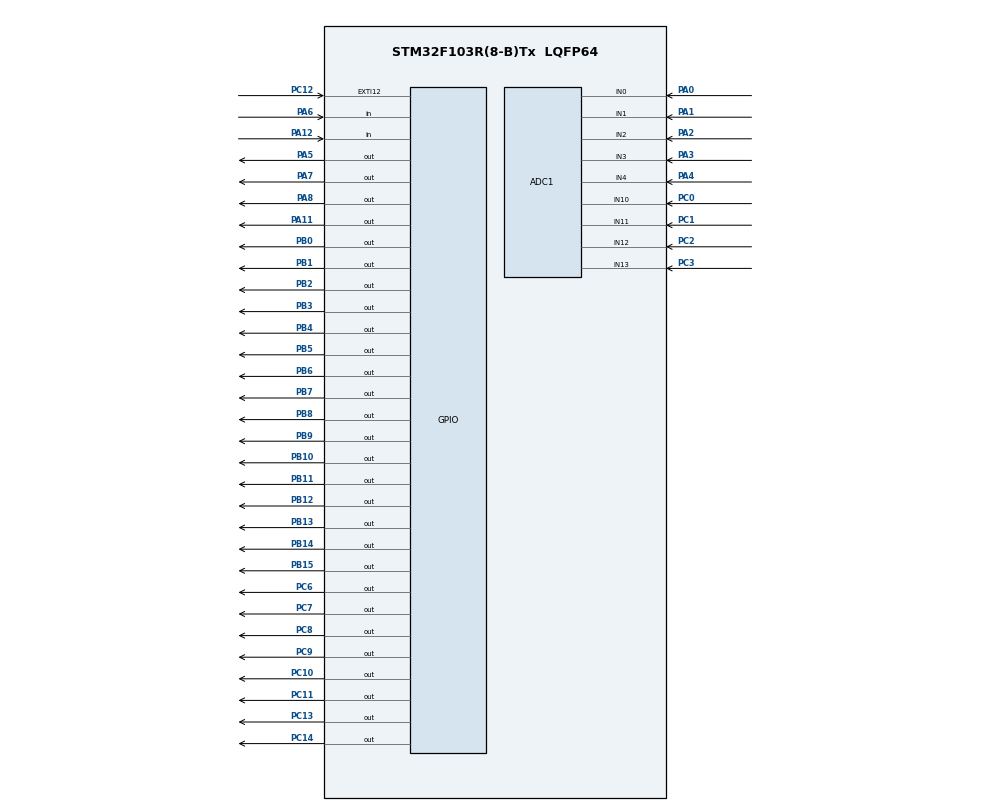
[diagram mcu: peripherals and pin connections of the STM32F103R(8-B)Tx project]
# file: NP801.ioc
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ADC1.Channel-0\#ChannelRegularConversion=ADC_CHANNEL_10
ADC1.Channel-1\#ChannelRegularConversion=ADC_CHANNEL_11
ADC1.Channel-2\#ChannelRegularConversion=ADC_CHANNEL_12
ADC1.Channel-3\#ChannelRegularConversion=ADC_CHANNEL_13
ADC1.Channel-4\#ChannelRegularConversion=ADC_CHANNEL_0
ADC1.Channel-5\#ChannelRegularConversion=ADC_CHANNEL_1
ADC1.Channel-6\#ChannelRegularConversion=ADC_CHANNEL_2
ADC1.Channel-7\#ChannelRegularConversion=ADC_CHANNEL_3
ADC1.Channel-8\#ChannelRegularConversion=ADC_CHANNEL_4
ADC1.ContinuousConvMode=ENABLE
ADC1.EnableAnalogWatchDog=false
ADC1.NbrOfConversion=9
ADC1.NbrOfConversionFlag=1
ADC1.Rank-0\#ChannelRegularConversion=1
ADC1.Rank-1\#ChannelRegularConversion=2
ADC1.Rank-2\#ChannelRegularConversion=3
ADC1.Rank-3\#ChannelRegularConversion=4
ADC1.Rank-4\#ChannelRegularConversion=5
ADC1.Rank-5\#ChannelRegularConversion=6
ADC1.Rank-6\#ChannelRegularConversion=7
ADC1.Rank-7\#ChannelRegularConversion=8
ADC1.Rank-8\#ChannelRegularConversion=9
ADC1.SamplingTime-0\#ChannelRegularConversion=ADC_SAMPLETIME_71CYCLES_5
ADC1.SamplingTime-1\#ChannelRegularConversion=ADC_SAMPLETIME_71CYCLES_5
ADC1.SamplingTime-2\#ChannelRegularConversion=ADC_SAMPLETIME_71CYCLES_5
ADC1.SamplingTime-3\#ChannelRegularConversion=ADC_SAMPLETIME_71CYCLES_5
ADC1.SamplingTime-4\#ChannelRegularConversion=ADC_SAMPLETIME_71CYCLES_5
ADC1.SamplingTime-5\#ChannelRegularConversion=ADC_SAMPLETIME_71CYCLES_5
ADC1.SamplingTime-6\#ChannelRegularConversion=ADC_SAMPLETIME_71CYCLES_5
ADC1.SamplingTime-7\#ChannelRegularConversion=ADC_SAMPLETIME_71CYCLES_5
ADC1.SamplingTime-8\#ChannelRegularConversion=ADC_SAMPLETIME_71CYCLES_5
ADC1.master=1
Dma.ADC1.0.Direction=DMA_PERIPH_TO_MEMORY
Dma.ADC1.0.Instance=DMA1_Channel1
Dma.ADC1.0.MemDataAlignment=DMA_MDATAALIGN_HALFWORD
Dma.ADC1.0.MemInc=DMA_MINC_ENABLE
Dma.ADC1.0.Mode=DMA_CIRCULAR
Dma.ADC1.0.PeriphDataAlignment=DMA_PDATAALIGN_HALFWORD
Dma.ADC1.0.PeriphInc=DMA_PINC_DISABLE
Dma.ADC1.0.Priority=DMA_PRIORITY_HIGH
Dma.Request0=ADC1
Mcu.Family=STM32F1
Mcu.Name=STM32F103R(8-B)Tx
Mcu.Package=LQFP64
NVIC.DMA1_Channel1_IRQn=true\:0\:0\:false\:false\:true
NVIC.EXTI15_10_IRQn=true\:1\:0\:true\:false\:true
NVIC.PriorityGroup=NVIC_PRIORITYGROUP_2
PA0-WKUP.Signal=ADCx_IN0
PA1.Signal=ADCx_IN1
PA11.GPIO_ModeDefaultOutputPP=GPIO_MODE_OUTPUT_OD
PA11.GPIO_Speed=GPIO_SPEED_FREQ_HIGH
PA11.PinState=GPIO_PIN_SET
PA11.Signal=GPIO_Output
PA12.GPIO_PuPd=GPIO_PULLUP
PA12.Signal=GPIO_Input
PA13.Mode=Serial_Wire
PA13.Signal=SYS_JTMS-SWDIO
PA14.Mode=Serial_Wire
PA14.Signal=SYS_JTCK-SWCLK
PA2.Signal=ADCx_IN2
PA3.Signal=ADCx_IN3
PA4.Signal=ADCx_IN4
PA5.GPIO_Speed=GPIO_SPEED_FREQ_HIGH
PA5.Signal=GPIO_Output
PA6.GPIO_PuPd=GPIO_PULLUP
PA6.Signal=GPIO_Input
PA7.GPIO_Speed=GPIO_SPEED_FREQ_HIGH
PA7.Signal=GPIO_Output
PA8.GPIO_Speed=GPIO_SPEED_FREQ_MEDIUM
PA8.PinState=GPIO_PIN_SET
PA8.Signal=GPIO_Output
PB0.GPIO_Speed=GPIO_SPEED_FREQ_HIGH
PB0.PinState=GPIO_PIN_RESET
PB0.Signal=GPIO_Output
PB1.GPIO_Speed=GPIO_SPEED_FREQ_HIGH
PB1.PinState=GPIO_PIN_RESET
PB1.Signal=GPIO_Output
PB10.GPIO_Speed=GPIO_SPEED_FREQ_HIGH
PB10.PinState=GPIO_PIN_RESET
PB10.Signal=GPIO_Output
PB11.GPIO_Speed=GPIO_SPEED_FREQ_HIGH
PB11.PinState=GPIO_PIN_RESET
PB11.Signal=GPIO_Output
PB12.GPIO_Speed=GPIO_SPEED_FREQ_HIGH
PB12.PinState=GPIO_PIN_RESET
PB12.Signal=GPIO_Output
PB13.GPIO_Speed=GPIO_SPEED_FREQ_HIGH
PB13.PinState=GPIO_PIN_RESET
PB13.Signal=GPIO_Output
PB14.GPIO_Speed=GPIO_SPEED_FREQ_HIGH
PB14.PinState=GPIO_PIN_RESET
PB14.Signal=GPIO_Output
PB15.GPIO_ModeDefaultOutputPP=GPIO_MODE_OUTPUT_PP
PB15.GPIO_Speed=GPIO_SPEED_FREQ_HIGH
PB15.PinState=GPIO_PIN_RESET
PB15.Signal=GPIO_Output
PB2.GPIO_Speed=GPIO_SPEED_FREQ_HIGH
PB2.PinState=GPIO_PIN_RESET
PB2.Signal=GPIO_Output
PB3.GPIO_Speed=GPIO_SPEED_FREQ_HIGH
PB3.PinState=GPIO_PIN_RESET
PB3.Signal=GPIO_Output
PB4.GPIO_Speed=GPIO_SPEED_FREQ_HIGH
PB4.PinState=GPIO_PIN_RESET
PB4.Signal=GPIO_Output
PB5.GPIO_Speed=GPIO_SPEED_FREQ_HIGH
PB5.PinState=GPIO_PIN_RESET
PB5.Signal=GPIO_Output
PB6.GPIO_Speed=GPIO_SPEED_FREQ_HIGH
PB6.PinState=GPIO_PIN_RESET
PB6.Signal=GPIO_Output
PB7.GPIO_Speed=GPIO_SPEED_FREQ_HIGH
PB7.PinState=GPIO_PIN_RESET
PB7.Signal=GPIO_Output
PB8.GPIO_Speed=GPIO_SPEED_FREQ_HIGH
PB8.PinState=GPIO_PIN_RESET
PB8.Signal=GPIO_Output
PB9.GPIO_Speed=GPIO_SPEED_FREQ_HIGH
PB9.PinState=GPIO_PIN_RESET
PB9.Signal=GPIO_Output
PC0.Signal=ADCx_IN10
PC1.Signal=ADCx_IN11
PC10.GPIO_Speed=GPIO_SPEED_FREQ_MEDIUM
PC10.PinState=GPIO_PIN_SET
PC10.Signal=GPIO_Output
PC11.GPIO_Speed=GPIO_SPEED_FREQ_MEDIUM
PC11.PinState=GPIO_PIN_SET
PC11.Signal=GPIO_Output
PC12.GPIO_ModeDefaultEXTI=GPIO_MODE_IT_FALLING
PC12.GPIO_PuPd=GPIO_PULLUP
PC12.Signal=GPXTI12
PC13-TAMPER-RTC.Signal=GPIO_Output
PC14-OSC32_IN.Signal=GPIO_Output
PC2.Signal=ADCx_IN12
PC3.Signal=ADCx_IN13
PC6.GPIO_Speed=GPIO_SPEED_FREQ_HIGH
PC6.PinState=GPIO_PIN_SET
PC6.Signal=GPIO_Output
PC7.GPIO_Speed=GPIO_SPEED_FREQ_HIGH
PC7.PinState=GPIO_PIN_SET
PC7.Signal=GPIO_Output
PC8.GPIO_Speed=GPIO_SPEED_FREQ_HIGH
PC8.PinState=GPIO_PIN_SET
PC8.Signal=GPIO_Output
PC9.GPIO_Speed=GPIO_SPEED_FREQ_HIGH
PC9.PinState=GPIO_PIN_SET
PC9.Signal=GPIO_Output
PD0-OSC_IN.Mode=HSE-External-Oscillator
PD0-OSC_IN.Signal=RCC_OSC_IN
PD1-OSC_OUT.Mode=HSE-External-Oscillator
PD1-OSC_OUT.Signal=RCC_OSC_OUT
ProjectManager.HeapSize=0xA00
ProjectManager.StackSize=0x800
ProjectManager.TargetToolchain=MDK-ARM V4
RCC.ADCPresc=RCC_ADCPCLK2_DIV8
RCC.AHBFreq_Value=72000000
RCC.APB1CLKDivider=RCC_HCLK_DIV2
RCC.APB1Freq_Value=36000000
RCC.APB1TimFreq_Value=72000000
RCC.APB2Freq_Value=72000000
RCC.APB2TimFreq_Value=72000000
RCC.HCLKFreq_Value=72000000
RCC.HSIState=RCC_HSI_ON
RCC.PLLMUL=RCC_PLL_MUL9
RCC.PLLSourceVirtual=RCC_PLLSOURCE_HSE
RCC.SYSCLKFreq_VALUE=72000000
RCC.SYSCLKSource=RCC_SYSCLKSOURCE_PLLCLK
RCC.TimSys_Div=SYSTICK_CLKSOURCE_HCLK_DIV8
RCC.USBFreq_Value=72000000
SH.ADCx_IN0.0=ADC1_IN0,IN0
SH.ADCx_IN1.0=ADC1_IN1,IN1
SH.ADCx_IN10.0=ADC1_IN10,IN10
SH.ADCx_IN11.0=ADC1_IN11,IN11
SH.ADCx_IN12.0=ADC1_IN12,IN12
SH.ADCx_IN13.0=ADC1_IN13,IN13
SH.ADCx_IN2.0=ADC1_IN2,IN2
SH.ADCx_IN3.0=ADC1_IN3,IN3
SH.ADCx_IN4.0=ADC1_IN4,IN4
VP_CRC_VS_CRC.Mode=CRC_Activate
board=NP801

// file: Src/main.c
/**
  ******************************************************************************
  * File Name          : main.c
  * Description        : Main program body
  ******************************************************************************
  *
  * COPYRIGHT(c) 2016 STMicroelectronics
  *
  * Redistribution and use in source and binary forms, with or without modification,
  * are permitted provided that the following conditions are met:
  *   1. Redistributions of source code must retain the above copyright notice,
  *      this list of conditions and the following disclaimer.
  *   2. Redistributions in binary form must reproduce the above copyright notice,
  *      this list of conditions and the following disclaimer in the documentation
  *      and/or other materials provided with the distribution.
  *   3. Neither the name of STMicroelectronics nor the names of its contributors
  *      may be used to endorse or promote products derived from this software
  *      without specific prior written permission.
  *
  * THIS SOFTWARE IS PROVIDED BY THE COPYRIGHT HOLDERS AND CONTRIBUTORS "AS IS"
  * AND ANY EXPRESS OR IMPLIED WARRANTIES, INCLUDING, BUT NOT LIMITED TO, THE
  * IMPLIED WARRANTIES OF MERCHANTABILITY AND FITNESS FOR A PARTICULAR PURPOSE ARE
  * DISCLAIMED. IN NO EVENT SHALL THE COPYRIGHT HOLDER OR CONTRIBUTORS BE LIABLE
  * FOR ANY DIRECT, INDIRECT, INCIDENTAL, SPECIAL, EXEMPLARY, OR CONSEQUENTIAL
  * DAMAGES (INCLUDING, BUT NOT LIMITED TO, PROCUREMENT OF SUBSTITUTE GOODS OR
  * SERVICES; LOSS OF USE, DATA, OR PROFITS; OR BUSINESS INTERRUPTION) HOWEVER
  * CAUSED AND ON ANY THEORY OF LIABILITY, WHETHER IN CONTRACT, STRICT LIABILITY,
  * OR TORT (INCLUDING NEGLIGENCE OR OTHERWISE) ARISING IN ANY WAY OUT OF THE USE
  * OF THIS SOFTWARE, EVEN IF ADVISED OF THE POSSIBILITY OF SUCH DAMAGE.
  *
  ******************************************************************************
  */
#include "main.h"
#include "stm32f1xx_hal.h"

/* USER CODE BEGIN Includes */
extern volatile GUI_TIMER_TIME OS_TimeMS;
// volatile  uint8_t  istouch;

/* USER CODE END Includes */

ADC_HandleTypeDef hadc1;
DMA_HandleTypeDef hdma_adc1;

CRC_HandleTypeDef hcrc;

IWDG_HandleTypeDef hiwdg;

/* USER CODE BEGIN PV */
/* Private variables ---------------------------------------------------------*/
 #define OFFLIGHTTIME  50000

 #define LEN(a)          (sizeof(a) / sizeof(a[0]))
 enum
{
	display=0,
	alarm,

};
 static uint16_t delay[10],light=OFFLIGHTTIME;

/* USER CODE END PV */

void SystemClock_Config(void);
void Error_Handler(void);
static void MX_GPIO_Init(void);
static void MX_DMA_Init(void);
static void MX_ADC1_Init(void);
static void MX_CRC_Init(void);
static void MX_IWDG_Init(void);

/* USER CODE BEGIN PFP */
/* Private function prototypes -----------------------------------------------*/

/* USER CODE END PFP */

int main(void)
{

  /* MCU Configuration----------------------------------------------------------*/

  /* Reset of all peripherals, Initializes the Flash interface and the Systick. */
  HAL_Init();

  /* Configure the system clock */
  SystemClock_Config();

  /* Initialize all configured peripherals */
  MX_GPIO_Init();
  MX_DMA_Init();
  MX_ADC1_Init();
  MX_CRC_Init();
//  MX_IWDG_Init();

  /* USER CODE BEGIN 2 */

  MainTask();
  /* USER CODE END 2 */
  Tem_Init();
  /* Infinite loop */
  while (1)
  {
     GUI_PID_STATE State;
  /* USER CODE BEGIN 3 */
	 if(!delay[display]){
		delay[display] = 100;
        dispTemGraph();
	    dispTemPanel();
		if(GUI_TOUCH_GetState(&State)){
			if(!light) {
				lcdLight(16);
				HAL_GPIO_WritePin(GPIOC,GPIO_PIN_10,GPIO_PIN_RESET);
			}
			light = OFFLIGHTTIME;
		}
     }
	 if(!delay[alarm]) onAlarm();
  }
  /* USER CODE END 3 */

}

/** System Clock Configuration
*/
void SystemClock_Config(void)
{

  RCC_OscInitTypeDef RCC_OscInitStruct;
  RCC_ClkInitTypeDef RCC_ClkInitStruct;
  RCC_PeriphCLKInitTypeDef PeriphClkInit;

    /**Initializes the CPU, AHB and APB busses clocks
    */
  RCC_OscInitStruct.OscillatorType = RCC_OSCILLATORTYPE_LSI|RCC_OSCILLATORTYPE_HSE;
  RCC_OscInitStruct.HSEState = RCC_HSE_ON;
  RCC_OscInitStruct.HSEPredivValue = RCC_HSE_PREDIV_DIV1;
  RCC_OscInitStruct.HSIState = RCC_HSI_ON;
  RCC_OscInitStruct.LSIState = RCC_LSI_ON;
  RCC_OscInitStruct.PLL.PLLState = RCC_PLL_ON;
  RCC_OscInitStruct.PLL.PLLSource = RCC_PLLSOURCE_HSE;
  RCC_OscInitStruct.PLL.PLLMUL = RCC_PLL_MUL9;
  if (HAL_RCC_OscConfig(&RCC_OscInitStruct) != HAL_OK)
  {
    Error_Handler();
  }

    /**Initializes the CPU, AHB and APB busses clocks
    */
  RCC_ClkInitStruct.ClockType = RCC_CLOCKTYPE_HCLK|RCC_CLOCKTYPE_SYSCLK
                              |RCC_CLOCKTYPE_PCLK1|RCC_CLOCKTYPE_PCLK2;
  RCC_ClkInitStruct.SYSCLKSource = RCC_SYSCLKSOURCE_PLLCLK;
  RCC_ClkInitStruct.AHBCLKDivider = RCC_SYSCLK_DIV1;
  RCC_ClkInitStruct.APB1CLKDivider = RCC_HCLK_DIV2;
  RCC_ClkInitStruct.APB2CLKDivider = RCC_HCLK_DIV2;

  if (HAL_RCC_ClockConfig(&RCC_ClkInitStruct, FLASH_LATENCY_2) != HAL_OK)
  {
    Error_Handler();
  }

  PeriphClkInit.PeriphClockSelection = RCC_PERIPHCLK_ADC;
  PeriphClkInit.AdcClockSelection = RCC_ADCPCLK2_DIV8;
  if (HAL_RCCEx_PeriphCLKConfig(&PeriphClkInit) != HAL_OK)
  {
    Error_Handler();
  }

    /**Configure the Systick interrupt time
    */
  HAL_SYSTICK_Config(HAL_RCC_GetHCLKFreq()/8000);

    /**Configure the Systick
    */
  HAL_SYSTICK_CLKSourceConfig(SYSTICK_CLKSOURCE_HCLK_DIV8);

  /* SysTick_IRQn interrupt configuration */
  HAL_NVIC_SetPriority(SysTick_IRQn, 0, 0);
}

/* ADC1 init function */
static void MX_ADC1_Init(void)
{

  ADC_ChannelConfTypeDef sConfig;

    /**Common config
    */
  hadc1.Instance = ADC1;
  hadc1.Init.ScanConvMode = ADC_SCAN_ENABLE;
  hadc1.Init.ContinuousConvMode = ENABLE;
  hadc1.Init.DiscontinuousConvMode = DISABLE;
  hadc1.Init.ExternalTrigConv = ADC_SOFTWARE_START;
  hadc1.Init.DataAlign = ADC_DATAALIGN_RIGHT;
  hadc1.Init.NbrOfConversion = 9;
  if (HAL_ADC_Init(&hadc1) != HAL_OK)
  {
    Error_Handler();
  }

    /**Configure Regular Channel
    */
  sConfig.Channel = ADC_CHANNEL_10;
  sConfig.Rank = 1;
  sConfig.SamplingTime = ADC_SAMPLETIME_71CYCLES_5;
  if (HAL_ADC_ConfigChannel(&hadc1, &sConfig) != HAL_OK)
  {
    Error_Handler();
  }

    /**Configure Regular Channel
    */
  sConfig.Channel = ADC_CHANNEL_11;
  sConfig.Rank = 2;
  if (HAL_ADC_ConfigChannel(&hadc1, &sConfig) != HAL_OK)
  {
    Error_Handler();
  }

    /**Configure Regular Channel
    */
  sConfig.Channel = ADC_CHANNEL_12;
  sConfig.Rank = 3;
  if (HAL_ADC_ConfigChannel(&hadc1, &sConfig) != HAL_OK)
  {
    Error_Handler();
  }

    /**Configure Regular Channel
    */
  sConfig.Channel = ADC_CHANNEL_13;
  sConfig.Rank = 4;
  if (HAL_ADC_ConfigChannel(&hadc1, &sConfig) != HAL_OK)
  {
    Error_Handler();
  }

    /**Configure Regular Channel
    */
  sConfig.Channel = ADC_CHANNEL_0;
  sConfig.Rank = 5;
  if (HAL_ADC_ConfigChannel(&hadc1, &sConfig) != HAL_OK)
  {
    Error_Handler();
  }

    /**Configure Regular Channel
    */
  sConfig.Channel = ADC_CHANNEL_1;
  sConfig.Rank = 6;
  if (HAL_ADC_ConfigChannel(&hadc1, &sConfig) != HAL_OK)
  {
    Error_Handler();
  }

    /**Configure Regular Channel
    */
  sConfig.Channel = ADC_CHANNEL_2;
  sConfig.Rank = 7;
  if (HAL_ADC_ConfigChannel(&hadc1, &sConfig) != HAL_OK)
  {
    Error_Handler();
  }

    /**Configure Regular Channel
    */
  sConfig.Channel = ADC_CHANNEL_3;
  sConfig.Rank = 1;
  if (HAL_ADC_ConfigChannel(&hadc1, &sConfig) != HAL_OK)
  {
    Error_Handler();
  }

    /**Configure Regular Channel
    */
  sConfig.Channel = ADC_CHANNEL_4;
  sConfig.Rank = 9;
  if (HAL_ADC_ConfigChannel(&hadc1, &sConfig) != HAL_OK)
  {
    Error_Handler();
  }
  if (HAL_ADCEx_Calibration_Start(&hadc1) != HAL_OK)
  {
    Error_Handler();
  }
}

/* CRC init function */
static void MX_CRC_Init(void)
{

  hcrc.Instance = CRC;
  if (HAL_CRC_Init(&hcrc) != HAL_OK)
  {
    Error_Handler();
  }

}

/* IWDG init function */
static void MX_IWDG_Init(void)
{

  hiwdg.Instance = IWDG;
  hiwdg.Init.Prescaler = IWDG_PRESCALER_256;
  hiwdg.Init.Reload = 4095;
  if (HAL_IWDG_Init(&hiwdg) != HAL_OK)
  {
    Error_Handler();
  }

}

static void MX_DMA_Init(void)
{
  /* DMA controller clock enable */
  __HAL_RCC_DMA1_CLK_ENABLE();

  /* DMA interrupt init */
  /* DMA1_Channel1_IRQn interrupt configuration */
  HAL_NVIC_SetPriority(DMA1_Channel1_IRQn, 0, 0);
  HAL_NVIC_EnableIRQ(DMA1_Channel1_IRQn);

}

/** Configure pins as
        * Analog
        * Input
        * Output
        * EVENT_OUT
        * EXTI
*/
static void MX_GPIO_Init(void)
{

  GPIO_InitTypeDef GPIO_InitStruct;

  /* GPIO Ports Clock Enable */
  __HAL_RCC_GPIOC_CLK_ENABLE();
  __HAL_RCC_GPIOD_CLK_ENABLE();
  __HAL_RCC_GPIOA_CLK_ENABLE();
  __HAL_RCC_GPIOB_CLK_ENABLE();

  /*Configure GPIO pin Output Level */
  HAL_GPIO_WritePin(GPIOC, GPIO_PIN_10|GPIO_PIN_13|GPIO_PIN_14, GPIO_PIN_RESET);

  /*Configure GPIO pin Output Level */
  HAL_GPIO_WritePin(GPIOA, GPIO_PIN_5|GPIO_PIN_7, GPIO_PIN_RESET);

  /*Configure GPIO pin Output Level */
  HAL_GPIO_WritePin(GPIOB, GPIO_PIN_0|GPIO_PIN_1|GPIO_PIN_2|GPIO_PIN_10
                          |GPIO_PIN_11|GPIO_PIN_12|GPIO_PIN_13|GPIO_PIN_14
                          |GPIO_PIN_15|GPIO_PIN_3|GPIO_PIN_4|GPIO_PIN_5
                          |GPIO_PIN_6|GPIO_PIN_7|GPIO_PIN_8|GPIO_PIN_9, GPIO_PIN_RESET);

  /*Configure GPIO pin Output Level */
  HAL_GPIO_WritePin(GPIOC, GPIO_PIN_6|GPIO_PIN_7|GPIO_PIN_8|GPIO_PIN_9
                          |GPIO_PIN_11, GPIO_PIN_SET);

  /*Configure GPIO pin Output Level */
  HAL_GPIO_WritePin(GPIOA, GPIO_PIN_8|GPIO_PIN_11, GPIO_PIN_SET);

  /*Configure GPIO pins : PC13 PC14 */
  GPIO_InitStruct.Pin = GPIO_PIN_13|GPIO_PIN_14;
  GPIO_InitStruct.Mode = GPIO_MODE_OUTPUT_PP;
  GPIO_InitStruct.Speed = GPIO_SPEED_FREQ_LOW;
  HAL_GPIO_Init(GPIOC, &GPIO_InitStruct);

  /*Configure GPIO pins : PA5 PA7 */
  GPIO_InitStruct.Pin = GPIO_PIN_5|GPIO_PIN_7;
  GPIO_InitStruct.Mode = GPIO_MODE_OUTPUT_PP;
  GPIO_InitStruct.Speed = GPIO_SPEED_FREQ_HIGH;
  HAL_GPIO_Init(GPIOA, &GPIO_InitStruct);

  /*Configure GPIO pins : PA6 PA12 */
  GPIO_InitStruct.Pin = GPIO_PIN_6|GPIO_PIN_12;
  GPIO_InitStruct.Mode = GPIO_MODE_INPUT;
  GPIO_InitStruct.Pull = GPIO_PULLUP;
  HAL_GPIO_Init(GPIOA, &GPIO_InitStruct);

  /*Configure GPIO pins : PB0 PB1 PB2 PB10
                           PB11 PB12 PB13 PB14
                           PB15 PB3 PB4 PB5
                           PB6 PB7 PB8 PB9 */
  GPIO_InitStruct.Pin = GPIO_PIN_0|GPIO_PIN_1|GPIO_PIN_2|GPIO_PIN_10
                          |GPIO_PIN_11|GPIO_PIN_12|GPIO_PIN_13|GPIO_PIN_14
                          |GPIO_PIN_15|GPIO_PIN_3|GPIO_PIN_4|GPIO_PIN_5
                          |GPIO_PIN_6|GPIO_PIN_7|GPIO_PIN_8|GPIO_PIN_9;
  GPIO_InitStruct.Mode = GPIO_MODE_OUTPUT_PP;
  GPIO_InitStruct.Speed = GPIO_SPEED_FREQ_HIGH;
  HAL_GPIO_Init(GPIOB, &GPIO_InitStruct);

  /*Configure GPIO pins : PC6 PC7 PC8 PC9 */
  GPIO_InitStruct.Pin = GPIO_PIN_6|GPIO_PIN_7|GPIO_PIN_8|GPIO_PIN_9;
  GPIO_InitStruct.Mode = GPIO_MODE_OUTPUT_PP;
  GPIO_InitStruct.Speed = GPIO_SPEED_FREQ_HIGH;
  HAL_GPIO_Init(GPIOC, &GPIO_InitStruct);

  /*Configure GPIO pin : PA8 */
  GPIO_InitStruct.Pin = GPIO_PIN_8;
  GPIO_InitStruct.Mode = GPIO_MODE_OUTPUT_PP;
  GPIO_InitStruct.Speed = GPIO_SPEED_FREQ_MEDIUM;
  HAL_GPIO_Init(GPIOA, &GPIO_InitStruct);

  /*Configure GPIO pin : PA11 */
  GPIO_InitStruct.Pin = GPIO_PIN_11;
  GPIO_InitStruct.Mode = GPIO_MODE_OUTPUT_OD;
  GPIO_InitStruct.Speed = GPIO_SPEED_FREQ_HIGH;
  HAL_GPIO_Init(GPIOA, &GPIO_InitStruct);

  /*Configure GPIO pins : PC10 PC11 */
  GPIO_InitStruct.Pin = GPIO_PIN_10|GPIO_PIN_11;
  GPIO_InitStruct.Mode = GPIO_MODE_OUTPUT_PP;
  GPIO_InitStruct.Speed = GPIO_SPEED_FREQ_MEDIUM;
  HAL_GPIO_Init(GPIOC, &GPIO_InitStruct);

  /*Configure GPIO pin : PC12 */
//  GPIO_InitStruct.Pin = GPIO_PIN_12;
//  GPIO_InitStruct.Mode = GPIO_MODE_IT_FALLING;
//  GPIO_InitStruct.Pull = GPIO_PULLUP;
//  HAL_GPIO_Init(GPIOC, &GPIO_InitStruct);

  /* EXTI interrupt init*/
//  HAL_NVIC_SetPriority(EXTI15_10_IRQn, 1, 1);
//  HAL_NVIC_EnableIRQ(EXTI15_10_IRQn);

}

void Error_Handler(void)
{
  while(1)
  {
  }
}

//----------------------------------------------------------------
void HAL_GPIO_EXTI_Callback(uint16_t GPIO_Pin)
{

}
//----------------------------------------------------------------
void HAL_SYSTICK_Callback(void)
{
	static uint8_t tim;
	for(int i=0;i<LEN(delay);i++)
	if(delay[i] >0) delay[i]--;
	OS_TimeMS++;
	if(++tim ==10){
        tim = 0;
	    GUI_TOUCH_Exec();
	}
	if(light >0) {
		light--;
		if(!light) {
			lcdLight(0);
			HAL_GPIO_WritePin(GPIOC,GPIO_PIN_10,GPIO_PIN_SET);
		}
	}
}
//----------------------------------------------------------------------
void onAlarm(void)
{
	static uint8_t bit;
	uint8_t Error;
	Error = 0;
    for(int i=0;i<8;i++){
		temperature[i].alarm = (temperature[i].PV10 > temperature[i].SV10) ? 1 : 0;
		if(temperature[i].alarm) Error = 1;
	}
    if(Error) HAL_GPIO_TogglePin(GPIOC,GPIO_PIN_10|GPIO_PIN_13);
	if((bit)&&(!Error)) HAL_GPIO_WritePin(GPIOC,GPIO_PIN_10|GPIO_PIN_13,GPIO_PIN_RESET);
    bit = Error;
	delay[alarm] = 400;//300ms
}

/************************ (C) COPYRIGHT STMicroelectronics *****END OF FILE****/
